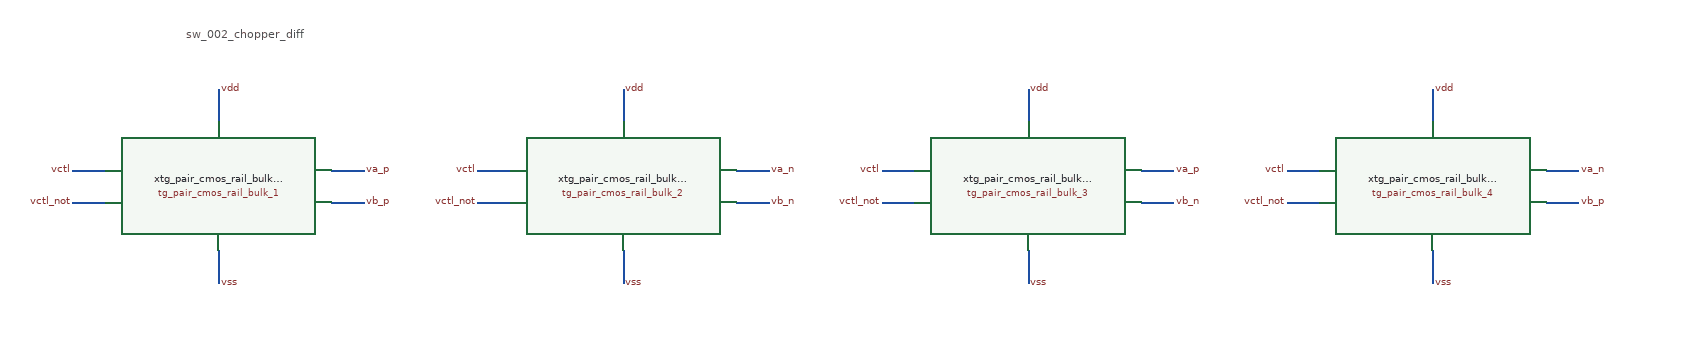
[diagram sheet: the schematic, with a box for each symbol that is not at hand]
v {xschem version=3.4.6 file_version=1.2}
G {}
K {}
V {}
S {}
E {}
T {sw_002_chopper_diff} -790 -200 0 0 0.4 0.4 {}
C {blocks/tg_pair_cmos_rail_bulk_1.sym} -750 0 0 0 {name=xtg_pair_cmos_rail_bulk_1}
C {blocks/tg_pair_cmos_rail_bulk_2.sym} -250 0 0 0 {name=xtg_pair_cmos_rail_bulk_2}
C {blocks/tg_pair_cmos_rail_bulk_3.sym} 250 0 0 0 {name=xtg_pair_cmos_rail_bulk_3}
C {blocks/tg_pair_cmos_rail_bulk_4.sym} 750 0 0 0 {name=xtg_pair_cmos_rail_bulk_4}
N -890 -20 -930 -20 {}
C {devices/lab_wire.sym} -930 -20 0 0 {name=l0 lab=vctl}
N -890 20 -930 20 {}
C {devices/lab_wire.sym} -930 20 0 0 {name=l1 lab=vctl_not}
N -610 -20 -570 -20 {}
C {devices/lab_wire.sym} -570 -20 0 1 {name=l2 lab=va_p}
N -610 20 -570 20 {}
C {devices/lab_wire.sym} -570 20 0 1 {name=l3 lab=vb_p}
N -750 -80 -750 -120 {}
C {devices/lab_wire.sym} -750 -120 0 1 {name=l4 lab=vdd}
N -750 80 -750 120 {}
C {devices/lab_wire.sym} -750 120 2 0 {name=l5 lab=vss}
N -390 -20 -430 -20 {}
C {devices/lab_wire.sym} -430 -20 0 0 {name=l6 lab=vctl}
N -390 20 -430 20 {}
C {devices/lab_wire.sym} -430 20 0 0 {name=l7 lab=vctl_not}
N -110 -20 -70 -20 {}
C {devices/lab_wire.sym} -70 -20 0 1 {name=l8 lab=va_n}
N -110 20 -70 20 {}
C {devices/lab_wire.sym} -70 20 0 1 {name=l9 lab=vb_n}
N -250 -80 -250 -120 {}
C {devices/lab_wire.sym} -250 -120 0 1 {name=l10 lab=vdd}
N -250 80 -250 120 {}
C {devices/lab_wire.sym} -250 120 2 0 {name=l11 lab=vss}
N 110 -20 70 -20 {}
C {devices/lab_wire.sym} 70 -20 0 0 {name=l12 lab=vctl}
N 110 20 70 20 {}
C {devices/lab_wire.sym} 70 20 0 0 {name=l13 lab=vctl_not}
N 390 -20 430 -20 {}
C {devices/lab_wire.sym} 430 -20 0 1 {name=l14 lab=va_p}
N 390 20 430 20 {}
C {devices/lab_wire.sym} 430 20 0 1 {name=l15 lab=vb_n}
N 250 -80 250 -120 {}
C {devices/lab_wire.sym} 250 -120 0 1 {name=l16 lab=vdd}
N 250 80 250 120 {}
C {devices/lab_wire.sym} 250 120 2 0 {name=l17 lab=vss}
N 610 -20 570 -20 {}
C {devices/lab_wire.sym} 570 -20 0 0 {name=l18 lab=vctl}
N 610 20 570 20 {}
C {devices/lab_wire.sym} 570 20 0 0 {name=l19 lab=vctl_not}
N 890 -20 930 -20 {}
C {devices/lab_wire.sym} 930 -20 0 1 {name=l20 lab=va_n}
N 890 20 930 20 {}
C {devices/lab_wire.sym} 930 20 0 1 {name=l21 lab=vb_p}
N 750 -80 750 -120 {}
C {devices/lab_wire.sym} 750 -120 0 1 {name=l22 lab=vdd}
N 750 80 750 120 {}
C {devices/lab_wire.sym} 750 120 2 0 {name=l23 lab=vss}
